VERSION 5.7 ;
  NOWIREEXTENSIONATPIN ON ;
  DIVIDERCHAR "/" ;
  BUSBITCHARS "[]" ;
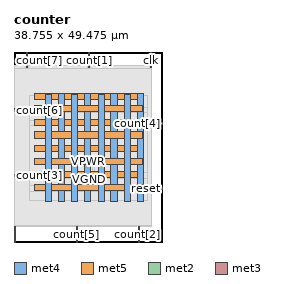
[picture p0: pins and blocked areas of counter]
MACRO counter
  CLASS BLOCK ;
  FOREIGN counter ;
  ORIGIN 0.000 0.000 ;
  SIZE 38.755 BY 49.475 ;
  PIN VGND
    DIRECTION INOUT ;
    USE GROUND ;
    PORT
      LAYER met4 ;
        RECT 11.465 10.640 13.065 38.760 ;
    END
    PORT
      LAYER met4 ;
        RECT 18.360 10.640 19.960 38.760 ;
    END
    PORT
      LAYER met4 ;
        RECT 25.255 10.640 26.855 38.760 ;
    END
    PORT
      LAYER met4 ;
        RECT 32.150 10.640 33.750 38.760 ;
    END
    PORT
      LAYER met5 ;
        RECT 5.280 16.775 33.750 18.375 ;
    END
    PORT
      LAYER met5 ;
        RECT 5.280 23.570 33.750 25.170 ;
    END
    PORT
      LAYER met5 ;
        RECT 5.280 30.365 33.750 31.965 ;
    END
    PORT
      LAYER met5 ;
        RECT 5.280 37.160 33.750 38.760 ;
    END
  END VGND
  PIN VPWR
    DIRECTION INOUT ;
    USE POWER ;
    PORT
      LAYER met4 ;
        RECT 8.165 10.640 9.765 38.320 ;
    END
    PORT
      LAYER met4 ;
        RECT 15.060 10.640 16.660 38.320 ;
    END
    PORT
      LAYER met4 ;
        RECT 21.955 10.640 23.555 38.320 ;
    END
    PORT
      LAYER met4 ;
        RECT 28.850 10.640 30.450 38.320 ;
    END
    PORT
      LAYER met5 ;
        RECT 5.280 13.475 33.360 15.075 ;
    END
    PORT
      LAYER met5 ;
        RECT 5.280 20.270 33.360 21.870 ;
    END
    PORT
      LAYER met5 ;
        RECT 5.280 27.065 33.360 28.665 ;
    END
    PORT
      LAYER met5 ;
        RECT 5.280 33.860 33.360 35.460 ;
    END
  END VPWR
  PIN clk
    DIRECTION INPUT ;
    USE SIGNAL ;
    ANTENNAGATEAREA 0.852000 ;
    PORT
      LAYER met2 ;
        RECT 35.510 45.475 35.790 49.475 ;
    END
  END clk
  PIN count[0]
    DIRECTION OUTPUT TRISTATE ;
    USE SIGNAL ;
    ANTENNADIFFAREA 0.795200 ;
    PORT
      LAYER met2 ;
        RECT 0.090 0.000 0.370 4.000 ;
    END
  END count[0]
  PIN count[1]
    DIRECTION OUTPUT TRISTATE ;
    USE SIGNAL ;
    ANTENNADIFFAREA 0.795200 ;
    PORT
      LAYER met2 ;
        RECT 19.410 45.475 19.690 49.475 ;
    END
  END count[1]
  PIN count[2]
    DIRECTION OUTPUT TRISTATE ;
    USE SIGNAL ;
    ANTENNADIFFAREA 0.795200 ;
    PORT
      LAYER met2 ;
        RECT 32.290 0.000 32.570 4.000 ;
    END
  END count[2]
  PIN count[3]
    DIRECTION OUTPUT TRISTATE ;
    USE SIGNAL ;
    ANTENNADIFFAREA 0.795200 ;
    PORT
      LAYER met3 ;
        RECT 0.000 17.040 4.000 17.640 ;
    END
  END count[3]
  PIN count[4]
    DIRECTION OUTPUT TRISTATE ;
    USE SIGNAL ;
    ANTENNADIFFAREA 0.795200 ;
    PORT
      LAYER met3 ;
        RECT 34.755 30.640 38.755 31.240 ;
    END
  END count[4]
  PIN count[5]
    DIRECTION OUTPUT TRISTATE ;
    USE SIGNAL ;
    ANTENNADIFFAREA 0.795200 ;
    PORT
      LAYER met2 ;
        RECT 16.190 0.000 16.470 4.000 ;
    END
  END count[5]
  PIN count[6]
    DIRECTION OUTPUT TRISTATE ;
    USE SIGNAL ;
    ANTENNADIFFAREA 0.795200 ;
    PORT
      LAYER met3 ;
        RECT 0.000 34.040 4.000 34.640 ;
    END
  END count[6]
  PIN count[7]
    DIRECTION OUTPUT TRISTATE ;
    USE SIGNAL ;
    ANTENNADIFFAREA 0.795200 ;
    PORT
      LAYER met2 ;
        RECT 3.310 45.475 3.590 49.475 ;
    END
  END count[7]
  PIN reset
    DIRECTION INPUT ;
    USE SIGNAL ;
    ANTENNAGATEAREA 0.213000 ;
    PORT
      LAYER met3 ;
        RECT 34.755 13.640 38.755 14.240 ;
    END
  END reset
  OBS
      LAYER li1 ;
        RECT 5.520 10.795 33.120 38.165 ;
      LAYER met1 ;
        RECT 0.070 10.640 35.810 38.320 ;
      LAYER met2 ;
        RECT 0.100 45.195 3.030 45.970 ;
        RECT 3.870 45.195 19.130 45.970 ;
        RECT 19.970 45.195 35.230 45.970 ;
        RECT 0.100 4.280 35.780 45.195 ;
        RECT 0.650 4.000 15.910 4.280 ;
        RECT 16.750 4.000 32.010 4.280 ;
        RECT 32.850 4.000 35.780 4.280 ;
      LAYER met3 ;
        RECT 4.000 35.040 34.755 38.245 ;
        RECT 4.400 33.640 34.755 35.040 ;
        RECT 4.000 31.640 34.755 33.640 ;
        RECT 4.000 30.240 34.355 31.640 ;
        RECT 4.000 18.040 34.755 30.240 ;
        RECT 4.400 16.640 34.755 18.040 ;
        RECT 4.000 14.640 34.755 16.640 ;
        RECT 4.000 13.240 34.355 14.640 ;
        RECT 4.000 10.715 34.755 13.240 ;
      LAYER met4 ;
        RECT 20.535 13.095 20.865 20.905 ;
  END
END counter
END LIBRARY

